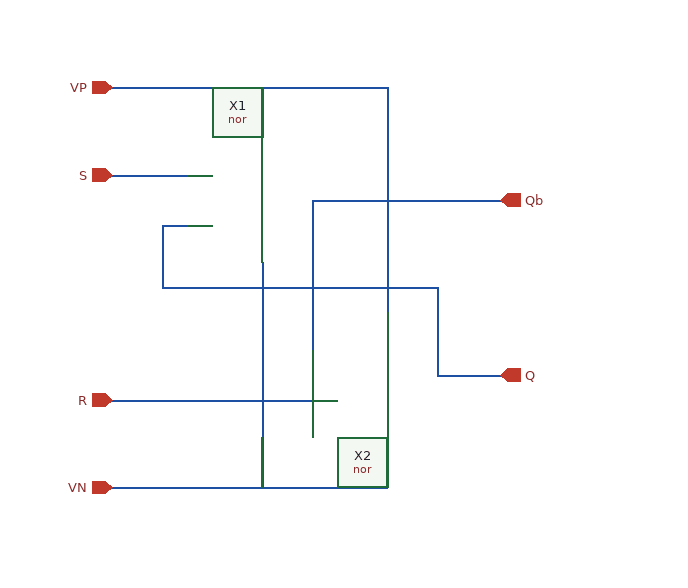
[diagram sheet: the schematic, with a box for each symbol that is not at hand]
v {xschem version=2.9.9 file_version=1.2 }
G {}
K {}
V {}
S {}
E {}
N 610 -150 640 -150 { lab=Q}
N 610 -290 640 -290 { lab=Qb}
N 450 -360 450 -340 { lab=VP}
N 350 -130 490 -130 { lab=#net2}
N 490 -290 490 -170 { lab=Qb}
N 590 -220 590 -150 { lab=Q}
N 370 -220 590 -220 { lab=Q}
N 370 -270 370 -220 { lab=Q}
N 370 -270 390 -270 { lab=Q}
N 550 -100 550 -80 { lab=VN}
N 550 -360 550 -200 { lab=VP}
N 450 -240 450 -80 { lab=VN}
N 350 -60 550 -60 { lab=VN}
N 490 -290 610 -290 { lab=Qb}
N 590 -150 610 -150 { lab=Q}
N 550 -380 550 -360 { lab=VP}
N 450 -380 450 -360 { lab=VP}
N 550 -80 550 -60 { lab=VN}
N 450 -80 450 -60 { lab=VN}
N 350 -310 370 -310 { lab=S}
N 330 -130 350 -130 { lab=R}
N 330 -60 350 -60 { lab=VN}
N 330 -310 350 -310 { lab=S}
N 330 -380 350 -380 { lab=VP}
N 370 -310 390 -310 {}
N 350 -380 550 -380 {}
C {devices/ipin.sym} 330 -310 0 0 {name=p1 lab=S}
C {devices/ipin.sym} 330 -130 0 0 {name=p2 lab=R}
C {devices/iopin.sym} 330 -380 2 0 {name=p3 lab=VP}
C {devices/iopin.sym} 330 -60 2 0 {name=p4 lab=VN}
C {devices/opin.sym} 640 -150 0 0 {name=p5 lab=Q}
C {devices/opin.sym} 640 -290 0 0 {name=p6 lab=Qb}
C {/home/madvlsi/Documents/MADVLSI_final/schematics/nor.sym} 350 -190 0 0 {name=X1}
C {/home/madvlsi/Documents/MADVLSI_final/schematics/nor.sym} 450 -50 0 0 {name=X2}
